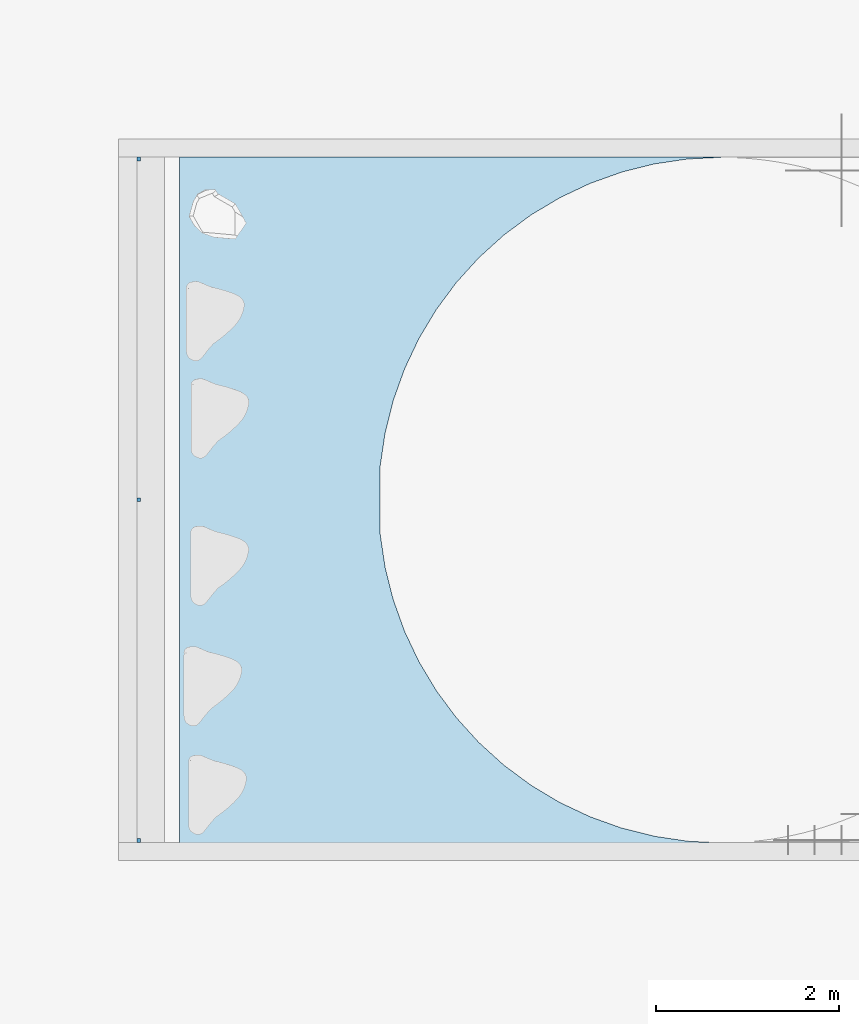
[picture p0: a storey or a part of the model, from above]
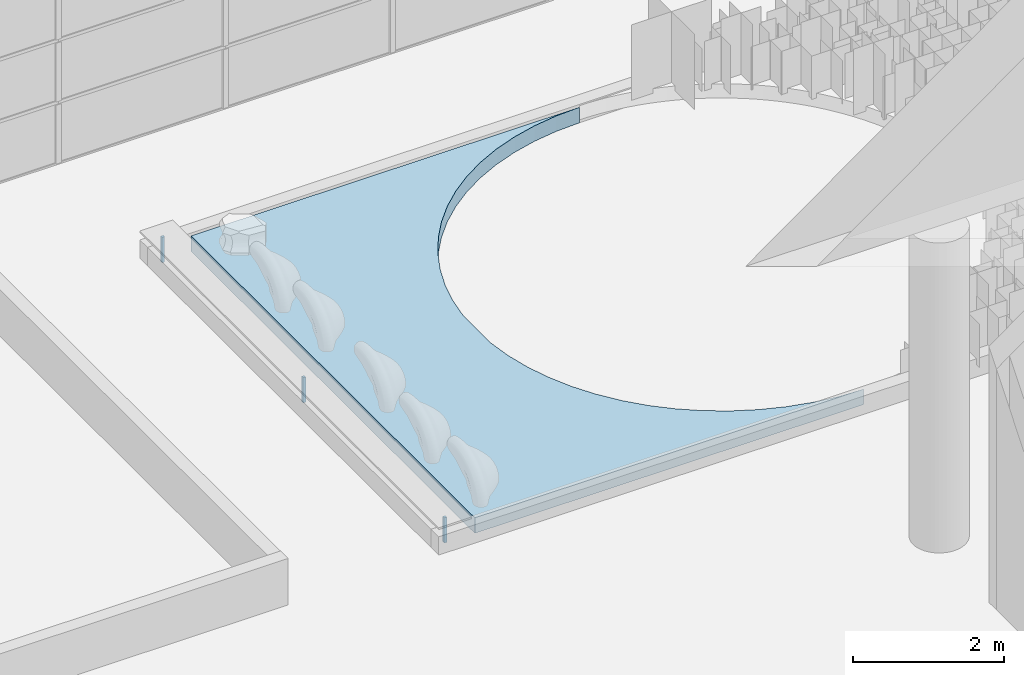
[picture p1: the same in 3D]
Properties of the parts of a building model (IFC4)

# File
Description: ViewDefinition [ReferenceView_V1.2], ExchangeRequirement[Architecture]
File name: Z:/1_Projekte/FFG TIKS Green BIM 2/AP6_Knowhow-Transfer/6.5 Winter School für Lernende im sekundären Bildungsbereich und in der Berufsausbildung/Gartenbauschule_3D_IFC_vwx/ArchiCAD_Berufsschule Gartenbau_v2_richtige Masse mir Begrünung_v5.ifc
Time: 2023-12-13T16:09:39
Author: Architect
Organization: Nemetschek Vectorworks, Inc.
Written by: Vectorworks Architect 2021 SP5 (Build 622768) (64-Bit) by Vectorworks, Inc.
Made in: Windows

# IfcSite, Default Site
RefLatitude: 48, 13, 0; RefLongitude: 16, 22, 0

# IfcBuilding, Default Building
Pset_BuildingCommon - SprinklerProtection: no; SprinklerProtectionAutomatic: no; NumberOfStoreys: 2; IsLandmarked: no

# IfcBuildingStorey (2)
In: Default Building
Pset_BuildingStoreyCommon - EntranceLevel: yes; AboveGround: yes; SprinklerProtection: yes; GrossPlannedArea: 0 m2
Name | Elevation (mm) | SprinklerProtectionAutomatic
EG - Story | 3000 | no
OG - Story | 0 | yes

# IfcBuildingElementPart (2948)
Name | In | Material
211 x Bekleidung | EG - Story | Bekleidung
96 x Normalglas | EG - Story | Normalglas
238 x Blech | EG - Story | Blech
Bauteil | EG - Story | Bauteil
705 x Normalglas | OG - Story | Normalglas
1696 x Blech | OG - Story | Blech
Bauteil | OG - Story | Bauteil

# IfcColumn (10)
Material: Tragende Bauteile
ArchiCADProperties - Absolutes Geschoss für Oberkantenverknüpfung: Nicht verknüpft; Anzeigen auf Umbau-Filter: Alle relevanten Filter; Baustoff: Tragende Bauteile; Baustoff / Mehrschichtiger Aufbau / Profil / Schraffur: Tragende Bauteile; Baustoffe (Alle): Tragende Bauteile; Ebene: 150 Stütze; Element-Typ: Stütze; Erzeugen des Tragwerksanalyse-Modells: yes; Geschoss für Oberkantenverknüpfung: Nicht verknüpft; Geschützt: no; Lage: Nicht definiert; Neigungswinkel: 90 deg; Oberfläche Extrusion: Farbe weiß; Oberfläche Stirnseite: Farbe weiß; Relatives Geschoss für Oberkantenverknüpfung: Nicht verknüpft; Struktur-Typ: Einfach; Stütze Querschnitt: Kreisförmig; Stützen Neigungswinkel: 90 deg; Tragende Funktion: Tragende Elemente; Umbau-Status: Bestand
Pset_ColumnCommon - Slope: 90 deg; LoadBearing: yes
Name | In | Element ID = Hotlink und Element-ID = Überobjekt-ID | Oberfläche (Alle) | Ursprungsgeschoss Name | Ursprungsgeschoss Nummer | Reference
4 x Stütze-004 | EG - Story | Stütze-004 | Farbe weiß | OG | 1 | Tragende Bauteile D200
2 x Stütze-003 | OG - Story | Stütze-003 | Farbe weiß | EG | 0 | Tragende Bauteile D800
2 x Stütze-002 | OG - Story | Stütze-002 | Farbe weiß | EG | 0 | Tragende Bauteile D800
Stütze-001 | OG - Story | Stütze-001 | Farbe weiß | EG | 0 | Tragende Bauteile D800
Stütze-001 | OG - Story | Stütze-001 | Putz glatt weiß; Farbe weiß | EG | 0 | Tragende Bauteile D800

# IfcFurniture: Bank (4)
In: OG - Story
Type - Material: Default

# IfcFurniture: IfcFurnitureType
In: OG - Story
Type - Material: Default

# IfcGeographicElement: Agapanthus 'Purple Cloud' (60)
In: OG - Story
Material: Plant Material

# IfcGeographicElement: Contemporary Garden (265)
In: OG - Story
Type - Description: Styled Plant
Material: Plant Material
Name
61 x Russian Sage
74 x Hidcote Blue English Lavender
12 x Hidcote Lavender
8 x Annabelle Hydrangea
49 x Tufted Hair Grass
61 x 

# IfcGeographicElement: Deschampsia caespitosa (48)
In: OG - Story
Material: Plant Material

# IfcGeographicElement: Hydrangea arborescens 'Annabelle' (8)
In: OG - Story
Material: Plant Material

# IfcGeographicElement: Lavandula angustifolia 'Hidcote Blue' (72)
In: OG - Story
Material: Plant Material

# IfcGeographicElement: Lavandula angustifolia 'Hidcote' (12)
In: OG - Story
Material: Plant Material

# IfcGeographicElement: Perovskia atriplicifolia 'Blue Spire' (60)
In: OG - Story
Material: Plant Material

# IfcRailing (2)
In: EG - Story
ArchiCADProperties - Anzeigen auf Umbau-Filter: Alle relevanten Filter; Baustoffe (Alle): Bekleidung; Ebene: 450 Absturzsicherung; Element ID: Geländer - 001; Element-Typ: Geländer; Geschützt: no; Hotlink und Element-ID: Geländer - 001; Lage: Nicht definiert; Oberfläche (Alle): Farbe weiß; Tragende Funktion: Nicht definiert; Überobjekt-ID: Geländer - 001; Umbau-Status: Bestand; Ursprungsgeschoss Name: OG; Ursprungsgeschoss Nummer: 1

# IfcSlab (11)
Name | In | Material | Anzahl der Öffnungen | Anzeigen auf Umbau-Filter | Baustoff = Baustoff / Mehrschichtiger Aufbau / Profil / Schraffur = Baustoffe (Alle) | Deckschraffur | Ebene | Element ID = Hotlink und Element-ID = Überobjekt-ID | Element-Typ | Erzeugen des Tragwerksanalyse-Modells = LoadBearing | Geschützt | Lage | Lage der Referenzebene | Oberfläche (Alle) = Oberfläche Kante = Oberfläche oben = Oberfläche unten | Struktur-Typ | Tragende Funktion | Umbau-Status | Ursprungsgeschoss Name | Ursprungsgeschoss Nummer
Decke-002 | EG - Story | Bauteil | 0 | Alle relevanten Filter | Bauteil | Massiv 25 % | 210 Decke | Decke-002 | Decke | yes | no | Nicht definiert | Oben | Farbe weiß | Einfach | Tragende Elemente | Bestand | OG | 1
2 x Decke-005 | EG - Story | Bauteil | 0 | Alle relevanten Filter | Bauteil | Massiv 25 % | 210 Decke | Decke-005 | Decke | yes | no | Nicht definiert | Oben | Farbe weiß | Einfach | Tragende Elemente | Bestand | OG | 1
Decke-004 | EG - Story | Bauteil | 0 | Alle relevanten Filter | Bauteil | Massiv 25 % | 210 Decke | Decke-004 | Decke | yes | no | Nicht definiert | Oben | Farbe weiß | Einfach | Tragende Elemente | Bestand | OG | 1
2 x Decke-001 | OG - Story | Bauteil | 0 | Alle relevanten Filter | Bauteil | Massiv 25 % | 210 Decke | Decke-001 | Decke | yes | no | Nicht definiert | Oben | Farbe weiß | Einfach | Tragende Elemente | Bestand | EG | 0
Decke-003 | OG - Story | Bauteil | 0 | Alle relevanten Filter | Bauteil | Massiv 25 % | 210 Decke | Decke-003 | Decke | yes | no | Nicht definiert | Oben | Farbe weiß | Einfach | Tragende Elemente | Bestand | EG | 0
3 x IfcSlab | OG - Story | Default
IfcSlab | OG - Story | Default | Substratkoerper - Korngroesse: 3/8; organischer Gehalt: 15%

# IfcSlab: Contemporary Garden
In: OG - Story
Type - Description: Styled Landscape Area; PredefinedType: BASESLAB
Material: Mulch MT, Soil MT
Pset_SlabCommon - Reference: Contemporary Garden

# IfcSlab: Landscape Rock 03
In: OG - Story
Material: Default
Pflanzenbeet - Pflegebedarf: mittel; Wasserbedarf: 10 l/m2 pro Woche

# IfcSlab: Landscape Rock Exposed Med (5)
In: OG - Story
Material: Default
Pflanzenbeet - Pflegebedarf: mittel; Wasserbedarf: 10 l/m2 pro Woche

# IfcStair (2)
Pset_StairCommon - NumberOfRiser: 10; NumberOfTreads: 10; RiserHeight: 0.15 mm; WalkingLineOffset: 3 mm; RequiredHeadroom: 2.2 mm
Name | In
Treppe - 003 | EG - Story
Treppe - 001 | OG - Story

# IfcWall (37)
In: OG - Story
Name | Material | Absolutes Geschoss für Oberkantenverknüpfung | Anzahl der Öffnungen = Ursprungsgeschoss Nummer | Anzeigen auf Umbau-Filter | Außenseite Oberfläche = Innenseite Oberfläche = Oberfläche (Alle) = Oberfläche Kante | Baustoff = Baustoff / Mehrschichtiger Aufbau / Profil / Schraffur = Baustoffe (Alle) | Ebene | Element ID = Hotlink und Element-ID = Überobjekt-ID | Element-Typ | Geometriemethode | Geschoss für Oberkantenverknüpfung | Geschützt | Lage = Tragende Funktion | Lage der Referenzlinie | Neigungswinkel (deg) = Wand Äußerer Neigungswinkel (deg) = Wand Innerer Neigungswinkel (deg) | Relatives Geschoss für Oberkantenverknüpfung | Struktur-Typ | Umbau-Status | Ursprungsgeschoss Name | Wandkomplexität
Wand-001 | Bauteil | Nicht verknüpft | 0 | Alle relevanten Filter | Farbe weiß | Bauteil | 110 Wand Aussen | Wand-001 | Wand | Uni | Nicht verknüpft | no | Nicht definiert | Außen | 90 | Nicht verknüpft | Einfach | Bestand | EG | gerade
2 x Wand-003 | Bauteil | Nicht verknüpft | 0 | Alle relevanten Filter | Farbe weiß | Bauteil | 110 Wand Aussen | Wand-003 | Wand | Uni | Nicht verknüpft | no | Nicht definiert | Außen | 90 | Nicht verknüpft | Einfach | Bestand | EG | gerade
2 x Wand-004 | Bauteil | Nicht verknüpft | 0 | Alle relevanten Filter | Farbe weiß | Bauteil | 110 Wand Aussen | Wand-004 | Wand | Uni | Nicht verknüpft | no | Nicht definiert | Außen | 90 | Nicht verknüpft | Einfach | Bestand | EG | gerade
2 x Wand-005 | Bauteil | Nicht verknüpft | 0 | Alle relevanten Filter | Farbe weiß | Bauteil | 110 Wand Aussen | Wand-005 | Wand | Uni | Nicht verknüpft | no | Nicht definiert | Außen | 90 | Nicht verknüpft | Einfach | Bestand | EG | gerade
3 x Wand-006 | Bauteil | Nicht verknüpft | 0 | Alle relevanten Filter | Farbe weiß | Bauteil | 110 Wand Aussen | Wand-006 | Wand | Uni | Nicht verknüpft | no | Nicht definiert | Außen | 90 | Nicht verknüpft | Einfach | Bestand | EG | gerade
Wand-024 | Normalglas | Nicht verknüpft | 0 | Alle relevanten Filter | Glas Normalglas | Normalglas | 110 Wand Aussen | Wand-024 | Wand | Uni | Nicht verknüpft | no | Nicht definiert | Außen | 90 | Nicht verknüpft | Einfach | Bestand | EG | gerade
2 x Wand-007 | Bauteil | Nicht verknüpft | 0 | Alle relevanten Filter | Farbe weiß | Bauteil | 110 Wand Aussen | Wand-007 | Wand | Uni | Nicht verknüpft | no | Nicht definiert | Außen | 90 | Nicht verknüpft | Einfach | Bestand | EG | gerade
Wand-008 | Bauteil | Nicht verknüpft | 0 | Alle relevanten Filter | Farbe weiß | Bauteil | 110 Wand Aussen | Wand-008 | Wand | Uni | Nicht verknüpft | no | Nicht definiert | Außen | 90 | Nicht verknüpft | Einfach | Bestand | EG | gerade
Wand-009 | Bauteil | Nicht verknüpft | 0 | Alle relevanten Filter | Farbe weiß | Bauteil | 110 Wand Aussen | Wand-009 | Wand | Uni | Nicht verknüpft | no | Nicht definiert | Außen | 90 | Nicht verknüpft | Einfach | Bestand | EG | gerade
Wand-010 | Bauteil | Nicht verknüpft | 0 | Alle relevanten Filter | Farbe weiß | Bauteil | 110 Wand Aussen | Wand-010 | Wand | Uni | Nicht verknüpft | no | Nicht definiert | Außen | 90 | Nicht verknüpft | Einfach | Bestand | EG | gerade
Wand-011 | Bauteil | Nicht verknüpft | 0 | Alle relevanten Filter | Farbe weiß | Bauteil | 110 Wand Aussen | Wand-011 | Wand | Uni | Nicht verknüpft | no | Nicht definiert | Außen | 90 | Nicht verknüpft | Einfach | Bestand | EG | gerade
Wand-016 | Bauteil | Nicht verknüpft | 0 | Alle relevanten Filter | Farbe weiß | Bauteil | 110 Wand Aussen | Wand-016 | Wand | Uni | Nicht verknüpft | no | Nicht definiert | Außen | 90 | Nicht verknüpft | Einfach | Bestand | EG | gerade
Wand-002 | Bauteil | Nicht verknüpft | 0 | Alle relevanten Filter | Farbe weiß | Bauteil | 110 Wand Aussen | Wand-002 | Wand | Uni | Nicht verknüpft | no | Nicht definiert | Außen | 90 | Nicht verknüpft | Einfach | Bestand | EG | gerade
Wand-018 | Bauteil | OG | 0 | Alle relevanten Filter | Farbe weiß | Bauteil | 110 Wand Aussen | Wand-018 | Wand | Uni | Ursprung + 1 (OG) | no | Nicht definiert | Außen | 90 | Ursprung + 1 | Einfach | Bestand | EG | gerade
Wand-019 | Bauteil | Nicht verknüpft | 0 | Alle relevanten Filter | Farbe weiß | Bauteil | 110 Wand Aussen | Wand-019 | Wand | Uni | Nicht verknüpft | no | Nicht definiert | Außen | 90 | Nicht verknüpft | Einfach | Bestand | EG | gerade
Wand-020 | Bauteil | OG | 0 | Alle relevanten Filter | Farbe weiß | Bauteil | 110 Wand Aussen | Wand-020 | Wand | Uni | Ursprung + 1 (OG) | no | Nicht definiert | Außen | 90 | Ursprung + 1 | Einfach | Bestand | EG | gerade
Wand-021 | Bauteil | Nicht verknüpft | 0 | Alle relevanten Filter | Farbe weiß | Bauteil | 110 Wand Aussen | Wand-021 | Wand | Uni | Nicht verknüpft | no | Nicht definiert | Außen | 90 | Nicht verknüpft | Einfach | Bestand | EG | gerade
Wand-022 | Bauteil | Nicht verknüpft | 0 | Alle relevanten Filter | Farbe weiß | Bauteil | 110 Wand Aussen | Wand-022 | Wand | Uni | Nicht verknüpft | no | Nicht definiert | Außen | 90 | Nicht verknüpft | Einfach | Bestand | EG | gerade
Wand-023 | Normalglas | Nicht verknüpft | 0 | Alle relevanten Filter | Glas Normalglas | Normalglas | 110 Wand Aussen | Wand-023 | Wand | Uni | Nicht verknüpft | no | Nicht definiert | Außen | 90 | Nicht verknüpft | Einfach | Bestand | EG | gerade
Wand-026 | Bauteil | Nicht verknüpft | 0 | Alle relevanten Filter | Farbe weiß | Bauteil | 110 Wand Aussen | Wand-026 | Wand | Uni | Nicht verknüpft | no | Nicht definiert | Außen | 90 | Nicht verknüpft | Einfach | Bestand | EG | gerade
Wand-027 | Bauteil | Nicht verknüpft | 0 | Alle relevanten Filter | Farbe weiß | Bauteil | 110 Wand Aussen | Wand-027 | Wand | Uni | Nicht verknüpft | no | Nicht definiert | Außen | 90 | Nicht verknüpft | Einfach | Bestand | EG | gerade
Wand-028 | Bauteil | Nicht verknüpft | 0 | Alle relevanten Filter | Farbe weiß | Bauteil | 110 Wand Aussen | Wand-028 | Wand | Uni | Nicht verknüpft | no | Nicht definiert | Außen | 90 | Nicht verknüpft | Einfach | Bestand | EG | gerade
Wand-029 | Bauteil | Nicht verknüpft | 0 | Alle relevanten Filter | Farbe weiß | Bauteil | 110 Wand Aussen | Wand-029 | Wand | Uni | Nicht verknüpft | no | Nicht definiert | Außen | 90 | Nicht verknüpft | Einfach | Bestand | EG | gerade
8 x IfcWall | Default

# IfcWindow (11)
In: OG - Story
OverallHeight: 600 mm; OverallWidth: 7500 mm; PredefinedType: WINDOW; Material: Default
AC_Pset_Ganzglasfenster_26 - 2D & 3D Öffnungslinien-Stift (or_iOpLinePen): 1; 2D-Darstellung (bShowMounting2D): yes; 2D-Detaillierungsgrad: 2; 2D-Fixpunkte in 3D zeigen: no; 2D-Symbol zeigen: yes; 3D: 8; 3D-Öffnungswinkel: 180 deg; Abdeckung Schraffur: Massiv 100 %; Abdeckungstyp (gs_slidingShutter_cover): Z-Profil; Abdeckungstyp (gs_slidingShutter_iCover): 1; Abdichtungsstreifen Zeige: yes; Absatz horizontal (mm) (gs_PlanViewInfos_T1_xOffsetMM): 3; Absatz horizontal (mm) (gs_PlanViewInfos_T2_xOffsetMM): -1; Absatz horizontal (mm) (gs_PlanViewInfos_T3_xOffsetMM): -1; Absatz horizontal (mm) (gs_PlanViewInfos_T4_xOffsetMM): 1; Absatz horizontal (mm) (gs_PlanViewInfos_T5_xOffsetMM): 0; Absatz horizontal (mm) (gs_PlanViewInfos_T6_xOffsetMM): 3; Absatz vertikal (mm) (gs_PlanViewInfos_T1_yOffsetMM): 2; Absatz vertikal (mm) (gs_PlanViewInfos_T2_yOffsetMM): 2; Absatz vertikal (mm) (gs_PlanViewInfos_T3_yOffsetMM): 0; Absatz vertikal (mm) (gs_PlanViewInfos_T4_yOffsetMM): 0; Absatz vertikal (mm) (gs_PlanViewInfos_T5_yOffsetMM): -3; Absatz vertikal (mm) (gs_PlanViewInfos_T6_yOffsetMM): -3; Abschlussart automatisch verändert: no; Aktivierte Sonnenschutz-Typen: 254; Anschlag im Grundriss zeigen: 1; Anschlagstyp (gs_reveal_doubleInnerTypeInt): 0; Anschlagstyp (gs_reveal_doubleOuterTypeInt): 0; Anschlagstyp (gs_reveal_type_int): 1; Anschlagstyp (gs_reveal_type_new): Keine Laibung - Ecke; Anschlagtiefe und Laibungswinkel gleich: yes; Anschluss Links: no; Anschluss oben: no; Anschluss Rechts: no; Anschluss unten: no; Anzahl Lamellen: 2; Anzahl Paneelen 2: 1; Anzeige-Standards Code - 2:GER, 3:CHE, 4:AUT: 4; Architekturlichte als Nominalmaß einstellen: yes; Ausrichtung Schraffur: 1; Außenkante: Lotrecht; Außenverkleidung: no; Außenverkleidung Oberflächenmaterial: Farbe grau DB 701; Außenwinkel obere Seite: 20 deg; Außenwinkel Seite: 20 deg; Außenwinkel Seite 2: 20 deg; Außenwinkel untere Seite: 20 deg; Äußerer Laibungstyp: ohne Anschlag; Aussparung Flügelrahmen unten in Kämpferfeld: yes; autom. Fenster ID Nummer: yes; autom. Hintersturzhöhe: no; Automat. Zeilenabstand: no; Automatische Breite und Höhe: yes; Automatische Einstellungen: yes; Automatische Maße: yes; Automatische Rollladenbreite: yes; Automatische Rollladenhöhe: yes; automatischer Schichteinzug Putz außen: yes; automatischer Schichteinzug Putz innen: yes; Baurichtmaßgröße als Nominalmaß einstellen: no; Befestigung Oberflächenmaterial: Farbe grau DB 701; Bemaßungsfangpunkte in 2D: no; Beschriftung Fenstertyp: 1; Bogen Schnittschraffur-Vordergrundstift: Weiß; Hintergrund Objekte; Brandschutz Ausdruck: E; Breite: 750,00; Breite Wert: Architekturlichte Breite; Dämmung: no; Dämmung hinter Kasten: no; Dämmung Schnittschraffur: Sand SN5; Dämmung Schnittschraffur-Hintergrundstift: Weiß; Hintergrund Objekte; Dämmung Schraffur: Beton unbewehrt SN47; Dämmung Schraffur 1: Beton unbewehrt SN47; Dämmung Schraffur 2: Beton unbewehrt SN47; Dämmung unter Fensterbank: yes; Dämmungsstreifen einfügen: yes; Darstellung als Oberlicht: no; Detaillierungsgrad in 3D Rollsicht Fensterbank: 1; Dicke des Schichteinzugs: 1; Drehwinkel: 0 deg; Eckanschluss Typ 1: 1; Eckanschluss Typ 2: 1; Ecke 1: no; Ecke 2: no; Eckfenster Debugfunktion: no; Eckfenster Funktion: yes; Eck-Profil: no; Eckwinkel: 90 deg; Editierbare Sprossen: no; Editierte Anschlagseite: 1; Editierte Schichtanzahl: 1; Editierte Wandseite: 1; Eigener Text: Eigene ID; Eigenes Nischen-Oberflächenmaterial: no; Eigenes Oberflächenmaterial: no; Einbaurahmen: no; Einbaurahmen Hintergrundstift: Weiß; Hintergrund Objekte; Einbaurahmen Konturlinientyp: 1; Einbaurahmen Oberflächenmaterial: Holz Esche; Einbaurahmen Schraffur (gs_mountingFrame_fill): Leer; Einbaurahmen Schraffur (gs_TolerBlin_fill_type): Leer; Einbaurahmen Schraffur-Hintergrundstift: Weiß; Hintergrund Objekte; Einbaurahmen Schraffur-Vordergrundstift (gs_mountingFrame_pen_: Weiß; Hintergrund Objekte; einheitliche Einfassungsbreiten (gs_trim_inside_uniform): yes; einheitliche Einfassungsbreiten (gs_trim_outside_uniform): yes; Einheitliche Oberflächen Verkleidung: yes; Einzuziehende Schichten: 1; Extra Rahmen: no; Falz: no; Faschen Links: no; Faschen Oben: no; Faschen Rechts: no; Faschen Unten: no; Faschentiefe >= Anschlagstiefe: no; Fenster Ausrichtung Definition: 0; Fenster gehört zum Raum, in den es öffnet: no; Fensterbank Außen: no; Fensterbank gebogen in gebogenen Wänden: yes; Fensterbank Hintergrundschraffur: yes; Fensterbank in Polygonwänden (iBoardInPolyWall): 2; Fensterbank in Polygonwänden (iLintelBoardInPolyWall): 2; Fensterbank Innen: no; Fensterbank Innen Hintergrundschraffur: no; Fensterbank innen ist gebogen: yes; Fensterbank ist gebogen in gebogenen Wänden: yes; Fensterbank Oberflächenmaterial: Naturstein Kalkstein; Fensterbank Schnittschraffur: Leer; Fensterbank Schnittschraffurhintergrundstift: Weiß; Hintergrund Objekte; Fensterbank Schnittschraffur-Vordergrundstift: Weiß; Hintergrund Objekte; Fensterbank Schraffur: Leer; Fensterbank Typ: 8; Fenster-Befestigungstyp: 1; Fensterbrett Oberflächenmaterial: Holz Nussbaum; Fenstereinfassung: no; Fensterkoten: yes; Fensterladen Oberflächenmaterial: Holz Esche; Fensterladenrahmen Oberflächenmaterial: Holz Esche; Fensternische Größen (gs_parapet_sizes_st): Automatisch; Fensternische Größen (iParapetSize): 1; Fensternischenunterkante bei (gs_parapet_bottom_st): Aktuellem Geschoss; Fensternischenunterkante bei (iParapetBottom): 1; Fensterrahmen Oberflächenmaterial außen: Farbe grau DB 701; Fensterrahmen Oberflächenmaterial innen: Farbe grau DB 701; Fertigparapet: 1; Fixpunkte 0-Kein,1-2D,2-3D,3-Alle: 3; Flügelrahmen Oberflächenmaterial außen: Farbe grau DB 701; Flügelrahmen Oberflächenmaterial innen: Farbe grau DB 701; Fugenfüllung Schraffur: Leer; Fugenfüllung Schraffur-Hintergrundstift: Weiß; Hintergrund Objekte; Führungsschienen: yes; Futter Außen (gs_trimtype_out): Rechteckig; Futter Außen (gs_trimtype_out_int): 1; Futter Innen (gs_trimtype_in): Rechteckig; Futter Innen (gs_trimtype_in_int): 1; Gehäuse Grifftyp: 1; Gehäuseunterseite außen: yes; Geöffnetes Gehäuse: yes; Gesamtglasfläche (gs_list_glassarea): 4.5; Gesamtglasfläche (gs_list_glassarea_tmp): 0; Gewicht: 0; Gewichtseinheit: kg; Glas Schnittschraffur: Leer; Glas Schnittschraffur-Hintergrundstift: Weiß; Hintergrund Objekte; Glas Schnittschraffur-Vordergrundstift: Weiß; Hintergrund Objekte; Grundriss: 1; Grundriss Info: 3; Grundrissdarstellungsoption: 3; Gruppe (FM_Type): Fenster; Gruppe (iFMType): 999; Hauptflügel eigener Flügel: no; Heizkörpernische: no; Hinterer Sturz Oberflächenmaterial: Farbe weiß; Hinterer Sturz übernimmt Oberflächenmaterial der Wand: yes; Hintersturz: no; Hintersturz Schraffur (efsc_h): Massiv 100 %; Hintersturz Schraffur (gs_hsturz_fillType): Massiv 100 %; Hintersturz Schraffur-Hintergrundstift: Weiß; Hintergrund Objekte; Hintersturz Schraffur-Vordergrundstift: Graustufen; Höhe Wert: Architekturlichte Höhe; ID-Nummer Wert: 0; IFC Betrieb (ifc_optype): 1; IFC Betrieb (ifc_optypestr): Einzel; in 3D geöffnet: yes; in 3D zeigen: no; Innenverkleidung: no; Innenverkleidung Oberflächenmaterial: Farbe grau DB 701; Jalousiekasten Oberflächenmaterial: Metall Chrom; Jalousielamellen Oberflächenmaterial: Lack schwarz; Jalousien Platzierung (gs_shutLam_iPlacement): 1; Jalousien Platzierung (gs_shutLam_placement): Vor Fassade angebracht; Kasten Typ (gs_shutRoll_boxType): Rechteckig; Kasten Typ (gs_shutRoll_iBoxType): 1; KastenBreite (gs_shutRoll_boxDefaultSize): Architekturlichte Breite; KastenBreite (gs_shutRoll_iBoxDefaultSize): 1; Kippwinkel der Lamellen (gs_shutLam_rotation): 45 deg; Kippwinkel der Lamellen (gs_shutLam2_rotation): 45 deg; Konstruktionstyp: 8; Kontur-Linientyp (gs_ltJoint): 1; Kontur-Linientyp (gs_ltPlug): 1; Kontur-Stift (gs_penJoint): Graustufen; Kontur-Stift (gs_penPlug): Graustufen; Laibung Ankerposition: 2; Laibung bearbeiten von (gs_reveal_angle_edit_by): Winkel und Tiefe; Laibung bearbeiten von (gs_reveal_angle_edit_by_int): 1; Laibungstyp Innen: ohne Anschlag; Letzte ausgewählte Seite: no; Linien-Ausrichtung (or_iOplineStyle): 1; Linien-Ausrichtung (or_oplineStyle): Griff; Linientyp: 4; Linientyp Gegenüberliegende Seite (or_iOpLineType3dOut): 1; Linientyp Gegenüberliegende Seite (or_opLineType3dOut): Strichlinie; Linientyp Grundriss: 4; Linientyp Kontur Fugenausfüllung: 1; Linientyp Öffnungsseite (or_iOpLineType3dIn): 0; Linientyp Öffnungsseite (or_opLineType3dIn): Volllinie; Loch hat das Oberflächenmaterial der Wandseite: yes; Lochanzahl horizontal: 5; Lochanzahl vertikal: 8; Marker spiegeln: yes; Massstab (gs_Etikett_scaleValues_m): 2; Massstab (gs_IDText_scaleValues_m): 2; Massstab (gs_PlanViewInfos_scaleValues_m): 2; Mauerwerksbogen Mörtel Oberflächenmaterial: Putz rauh grau; Mauerwerksbogen Schlusstein Oberflächenmaterial: Farbe grau; Mauerwerksbogen Stein Oberflächenmaterial: Farbe grau; Mauerwerksbrüstung Mörtel Oberflächenmaterial: Putz rauh grau; Mittelpfosten - Außenfläche: Farbe grau DB 701; Mittelpfosten - Innenfläche: Farbe grau DB 701; Modelldarstell. für 3D-Darstellung überschreiben: no; Modelldarstell. für symbolische 2D-Darstellung überschreiben: no; Mörtel Oberflächenmaterial: Putz rauh grau; Nebenflügel Linientyp: 1; Nebenflügel Linientyp in 3D: Strichlinie; Nebenöffnung Linientyp in 2D: 4; Neigung Kastendach: 10 deg; Nische unter d. Schicht: yes; Nischen-Oberflächenmaterial: Putz rauh gelb; Nominalmaß: 0; Num. of Horiz. Gitter Hauptflügel: 0; Num. of Horiz. Gitter oberes Feld: 0; Num. of Horiz. Gitter unteres Feld: 0; Num. of Vert. Gitter Hauptflügel: 0; Num. of Vert. Gitter oberes Feld: 0; Num. of Vert. Gitter unteres Feld: 0; Oberfläche: Holz Esche; Oberfläche Eckstütze: Farbe grau DB 701; Oberlicht eigener Flügel: no; Oberlichte (gs_kamp): no; Öffnung roh: 1; Öffnungslinie im Symbol zeigen: no; Öffnungslinie zeigen: yes; Öffnungslinien in 2D: yes; Öffnungslinien-Form (or_iSlidingType): 0; Öffnungslinien-Form (or_iSwingType): 1; Öffnungslinien-Form (or_SlidingType): Kein; Öffnungslinien-Form (or_SwingType): Gebogen; Öffnungslinien-Typ: 1; Öffnungsoberfläche ist gebogen in gebogenen Wänden: no; Öffnungsrichtung: 1; Öffnungstyp Hauptflügel: 1; Öffnungstyp Sprossenfenster: 1; Öffnungstyp Unterlicht: 1; Öffnungswinkel Hauptflügel 2D rechts: 0 deg; Öffnungswinkel Hauptflügel 3D: 0 deg; Öffnungswinkel Hauptflügel2 2D: 0 deg; Öffnungswinkel Sprossenfenster in 3D: 0 deg; Öffnungswinkel Unteres Feld in 3D: 0 deg; Paneel-Position (gs_shutter_iPanelPos): 1; Paneel-Position (gs_shutter_panelPos): Symmetrisch; Paneeltyp (gs_shutPanel_iType): 1; Paneeltyp (gs_shutPanel_type): Typ 1; Pfosten: no; Platz für Fußboden: no; Platzierungstyp (1=EF,0=F): no; Position X (mm): 0; Position Y (mm): 8; Preis: 0; Putz Oberflächenmaterial: Putz rauh grau; Putzschicht außen einziehen: 0; Putzschicht innen einziehen: 0; Querbalken oben: yes; Querbalken Typ oben: 1; Rahmen Deckschraffur: Leer; Rahmen Schnittschraffur: Leer; Rahmen Schraffur: Massiv 100 %; Rahmen Schraffur-Hintergrundstift (gs_penSash_bg): Weiß; Hintergrund Objekte; Rahmen Schraffur-Hintergrundstift (gs_penShCov_bg): Weiß; Hintergrund Objekte; Rahmen Schraffur-Vordergrundstift: Weiß; Hintergrund Objekte; Rahmenaußenmaß als Nominalmaß einstellen: no; Rahmenschneidung Schnittschraffur-Hintergrundstift: Weiß; Hintergrund Objekte; Rahmenschneidung Schnittschraffur-Vordergrundstift: Weiß; Hintergrund Objekte; Rohbauöffnung als Nominalmaß einstellen: no; Rohparapet: 1; Rolladenkasten in Wandöffnung: no; Rollladen Platzierung (gs_shutRoll_iPlacement): 1; Rollladen Platzierung (gs_shutRoll_placement): Vor Fassade angebracht; Rollladengehäuse Oberflächenmaterial: Metall Chrom; Rollladenlamellen Oberflächenmaterial: Lack schwarz; Rollladenschiene Oberflächenmaterial: Lack schwarz; Schicht als Putz ansehen: no; Schicht an Seite einziehen (gs_cavity_side): Beide; Schicht an Seite einziehen (iCavityClosureSide): 1; Schicht einziehen: no; Schicht einziehen zu Abschluss: no; Schichteinzug (gs_closure_type): Kein Schichteinzug; Schichteinzug (gs_closure_type_int): 1; Schichteinzug auf Seite 1: yes; Schichteinzug auf Seite 2: yes; Schichteinzug oben: no; Schichteinzug unten: no; Schichteinzug von Seite (gs_cc_dutch_ClosureToSide): 1; Schichteinzug zu Schicht: 1; Schichten von (gs_nTurnDir): Außenseite; Schichten von (iCavityClosureTurnDir): 1; Schiebladen Schiene Oberflächenmaterial: Metall Chrom; Schiene Position (gs_shutLam_iRailPos): 1; Schiene Position (gs_shutLam_railPos): Auf Verkleidung; Schiene Position (gs_shutRoll_iRailPos): 1; Schiene Position (gs_shutRoll_railPos): Auf Verkleidung; Schnitt / Ansicht: 1; Schnittschraffur (gs_faschen_fill): Diagonal 45; Schnittschraffur (gs_lintelboard_fill): Massiv 50 %; Schnittschraffur Bogen: Leer; Schnittschraffur-Hintergrunstift (gs_faschen_bg): Weiß; Hintergrund Objekte; Schnittschraffur-Hintergrunstift (gs_lintelboard_pen_bg): Weiß; Hintergrund Objekte; Schnittschraffur-Vordergrundstift Fensterbank innen: Weiß; Hintergrund Objekte; Schraffur (efsc2): Belag 2; Schraffur (gs_fillJoint): Leer; Schraffur (gs_fillPlug): Leer; Schraffur (gs_wallhole_fill): Leer; Schraffur Sturz vorne: Leer; Schraffur Zarge außen: Leer; Schraffur Zarge innen: Leer; Schraffurhg.-Stift Schnitt Fensterbank innen: Weiß; Hintergrund Objekte; Schraffur-Hintergrundstift (gs_board_wallhole_pen_bg): Weiß; Hintergrund Objekte; Schraffur-Hintergrundstift (gs_hgpenfillsturz_damm): Weiß; Hintergrund Objekte; Schraffur-Hintergrundstift (gs_pen_h): Weiß; Hintergrund Objekte; Schraffur-Hintergrundstift (gs_penJointBg): Graustufen; Schraffur-Hintergrundstift (gs_penPlugBg): Graustufen; Schraffur-Hintergrundstift (gs_sill_wallhole_pen_bg): Weiß; Hintergrund Objekte; Schraffur-Hintergrundstift (gs_wallhole_pen_bg): Weiß; Hintergrund Objekte; Schraffurhintergrundstift Bogen Schwelle: Weiß; Hintergrund Objekte; Schraffur-Hintergrundstift Zarge außen: Weiß; Hintergrund Objekte; Schraffur-Hintergrundstift Zarge innen: Weiß; Hintergrund Objekte; Schraffurstift Rahmen: Weiß; Hintergrund Objekte; Schraffur-Vordergrundstift Zarge außen: Weiß; Hintergrund Objekte; Schraffur-Vordergrundstift Zarge innen: Weiß; Hintergrund Objekte; Schriftgröße (mm): 1.5; Schriftgröße (papier) (gs_Etikett_fontSize_mm): 1.5; Schriftgröße (papier) (gs_IDText_fontSize_mm): 5; Schrifttyp (fontType): Arial; Schrifttyp (gs_IDText_fontType): Arial; Schrifttyp (gs_zsgri): Arial; Schwelle/Fenstereinfassung Übergröße: no; seitliche Wandkontur (gs_wallcontour): Beide; seitliche Wandkontur (gs_wallcontour_id): 1; Selbstschließend: no; Selbstschließend Index: 2; Sichtbarkeit Fensterbemaßung (gs_etikett): Modelldarstellungs-Optionen; Sichtbarkeit Fensterbemaßung (iEtikett): 3; Sonnenschutz (bSunshade): no; Sonnenschutz Schnittschraffur: Leer; Sonnenschutz Schnittschraffur-Hintergrundstift: Weiß; Hintergrund Objekte; Sonnenschutz Symbollinientyp: 1; Sonnenschutz Typ: 1; SSchnittschraffur Fensterbank innen: Leer; Stapelrichtung (gs_foldingShutter_iStacking): 1; Stapelrichtung (gs_foldingShutter_stacking): Innen; Stein Oberflächenmaterial: Mauerziegel Ziegel DF Läufer blaurot; Sturz (bMasonryArch): no; Sturz (gs_masonry_arch_int): 2; Sturz fertig: 1; Sturz Oberflächenmaterial: Farbe weiß; Sturz Schraffur: Beton unbewehrt SN47; Sturz Stift Hintergrund: Weiß; Hintergrund Objekte; Sturz über der Tür: yes; Sturz übernimmt Oberflächenmaterial der Wand: yes; Sturz/Schwelle im Grundriss zeigen: no; Sturzbrett: no; Sturzbrett Oberflächenmaterial: Farbe weiß; Sturzsystem: no; Sturztiefe Symbol- Linientyp: 21; Sturztiefe Symbolstift: dünn; Teilung Oberlichte: yes; Text (gs_PlanViewInfos_T5_customText): O; Text (gs_PlanViewInfos_T6_customText): Fest; Text (gs_textdrehkipp): DK; Text (gs_textkurbel): K; Text (gs_textll): RAF; Text (gs_textlr): FB; Text Anschlag 1: yes; Text Anschlag 2: yes; Text drehen (gs_dr1): no; Text drehen (gs_dr2): no; Text drehen (gs_dr3): no; Text drehen (gs_dr4): no; Text drehen (gs_PlanViewInfos_T5_Rotate): no; Text drehen (gs_PlanViewInfos_T6_Rotate): no; Text Drehkippflügel: yes; Text Drehkippflügel gespiegelt: yes; Text Elektro-Kurbel 2: no; Text Fertig Sturz: Sturz fertig; Text Fertigparapet: Fertigparapethöhe; Text gespiegelt (gs_PlanViewInfos_T5_Mirrored): yes; Text gespiegelt (gs_PlanViewInfos_T6_Mirrored): yes; Text Kurbel: yes; Text Kurbel gespiegelt: yes; Text Kurbel individuell: no; Text Öffnung roh: Öffnung roh; Text Position X (mm): 0; Text Position Y (mm): 8; Text Rohparapet: Rohparapethöhe; Texteinstellung (gs_Etikett_scaleValues): Maßstababhängig (Modellgrösse); Texteinstellung (gs_IDText_scaleValues): Maßstababhängig (Modellgrösse); Texteinstellung (gs_PlanViewInfos_scaleValues): Maßstababhängig (Modellgrösse); Trennlinie am Einzug: no; Typ: 1; Typ Faschen: 1; Typ Fassung: 2; Typ Links: 0; Typ Rechts: 0; Typ Sturz (gs_masonry_arch_structure): Verputzt; Typ Sturz (gs_masonry_arch_structure_int): 1; Übertrage aktuelle Nominal Größe auf die Auswahl: no; Umfang der Glasfläche: 0; Untere Laibung Typ (gs_reveal_type_bottom): ohne Anschlag; Untere Laibung Typ (gs_reveal_type_bottom_int): 2; Unteres Feld: no; Unteres Feld eigener Flügel: no; Unteres Feld geteilt: yes; Untersch. verb. Wände Stärke 1: no; Untersch. verb. Wände Stärke 2: no; Unterschiedliche Breiten (gs_stockb): no; Unterschiedliche Breiten (gs_ver_r): no; Unterschiedliche Rahmenbreite unten: no; Unterschiedliche Wandstärken: no; Verdeckte Brüstung Linientyp: 1; Verdeckte Brüstung zeigen: yes; Verglaste Fläche überschreiben: no; Verglasung -Oberflächenmaterial: Glas Normalglas; Verkleidung außen: yes; Verkleidung innen: yes; Verschattung Dämmung Schraffur: Leer; Voreingestellte Faschen - links: yes; Voreingestellte Faschen - rechts: yes; Wand hinter Kasten schneiden: yes; Wandbekleidung benutzen: no; Wand-Dämmschicht benutzen: no; Wandendlinie Linientyp: 4; Wandkontur (0-Keine,1-Voll,2-Seite,3-Länge): 0; Wandkontur (gs_wcont_line): beide Seiten; Wandkontur (iWallContourLine): 4; Wandkonturlinie außen - 1:100 und höher: yes; Wandkonturlinie außen - 1:50 und tiefer: yes; Wandkonturlinie innen - 1:100 und höher: yes; Wandkonturlinie innen - 1:50 und tiefer: yes; Wandkonturlinien Typ außen - 1:100 und höher: 1; Wandkonturlinien Typ außen - 1:50 and tiefer: 1; Wandkonturlinien Typ innen - 1:100 und höher: 1; Wandkonturlinien Typ innen - 1:50 und tiefer: 1; Wandquerschnittstyp: 1; Wandschraffur in der Öffnung: yes; Wandtyp: 1; Wärmedämmung Oberflächenmaterial: Putz glatt weiß; Winkel Ecke 1: 90 deg; Winkel Ecke 2: 90 deg; Winkel Fensterbank Außen: 3 deg; Winkel Fensterbank Innen: 0 deg; Winkel Lamelle: 30 deg; Winkel Neigung: 75 deg; Winkel oben: 20 deg; Winkel Öffnungsposition: 0 deg; Winkel Seite: 20 deg; Winkel Seite 2: 20 deg; Winkel unten: 20 deg; X Position (m): 0; Y Position (m): 0; Zeige die ID im Grundriss: no; Zeige nur die Grundriss Info: yes; zeige Verkleidung hinter Sonnenschutz (gs_shutLam_showCasingBe: yes; zeige Verkleidung hinter Sonnenschutz (gs_shutRoll_showCasingB: yes; Zeilenabstand (papier): 1; zu Raum ID außen Wert: Eigene; zu Raum ID innen Wert: Eigene; zus. Höhe: 60,00; Zusätzliche Werte zeigen (Öffnungsmass 1.20/1.50): yes
ArchiCADProperties - Anschlagsmaße: 7,50×0,60; Anzeigen auf Umbau-Filter: Alle relevanten Filter; Baustoff / Mehrschichtiger Aufbau / Profil / Schraffur: Leer; Bibliothekselement-Name: Ganzglasfenster 26; Ebene: 110 Wand Aussen; Element-Typ: Fenster; Geschützt: no; Größe laut Eingabe: 7,50×0,60; Größe Wandloch: 7,50×0,60; Lage: Nicht definiert; Marker-Text: <Eigener Text>; Name des Eigenschafts-Objekts: Fenster_Eig 26; Nominale B x H: 7,50×0,60; Nominale B x H x T: 7,50×0,60×0,47; Oberfläche (Alle): Glas Normalglas; Öffnung Bibliothekselementname: Ganzglasfenster 26; Öffnungsseite Schraffurindex: Leer; Schraffurtyp: Leer; Tragende Funktion: Nicht definiert; Umbau-Status: Bestand; Wandstruktur: Bauteil
Pset_WindowCommon - SmokeStop: no
Name | Fenster/Türnummer | Wandrichtungstyp | Element ID = Hotlink und Element-ID | Überobjekt-ID | Ursprungsgeschoss Name | Ursprungsgeschoss Nummer
2 x Fenster-002 | 2.2. Geschoss--Fenster-002 | 1 | Fenster-002 | Wand-002 | 2. Geschoss | 2
2 x Fenster-002 | 1.OG--Fenster-002 | 1 | Fenster-002 | Wand-002 | OG | 1
Fenster-002 | 3.3. Geschoss--Fenster-002 | 1 | Fenster-002 | Wand-002 | 3. Geschoss | 3
2 x Fenster-001 | 0.EG--Fenster-001 | 0 | Fenster-001 | Wand-018 | EG | 0
3 x Fenster-001 | 1.OG--Fenster-001 | 0 | Fenster-001 | Wand-018 | OG | 1
Fenster-001 | 2.2. Geschoss--Fenster-001 | 0 | Fenster-001 | Wand-018 | 2. Geschoss | 2
